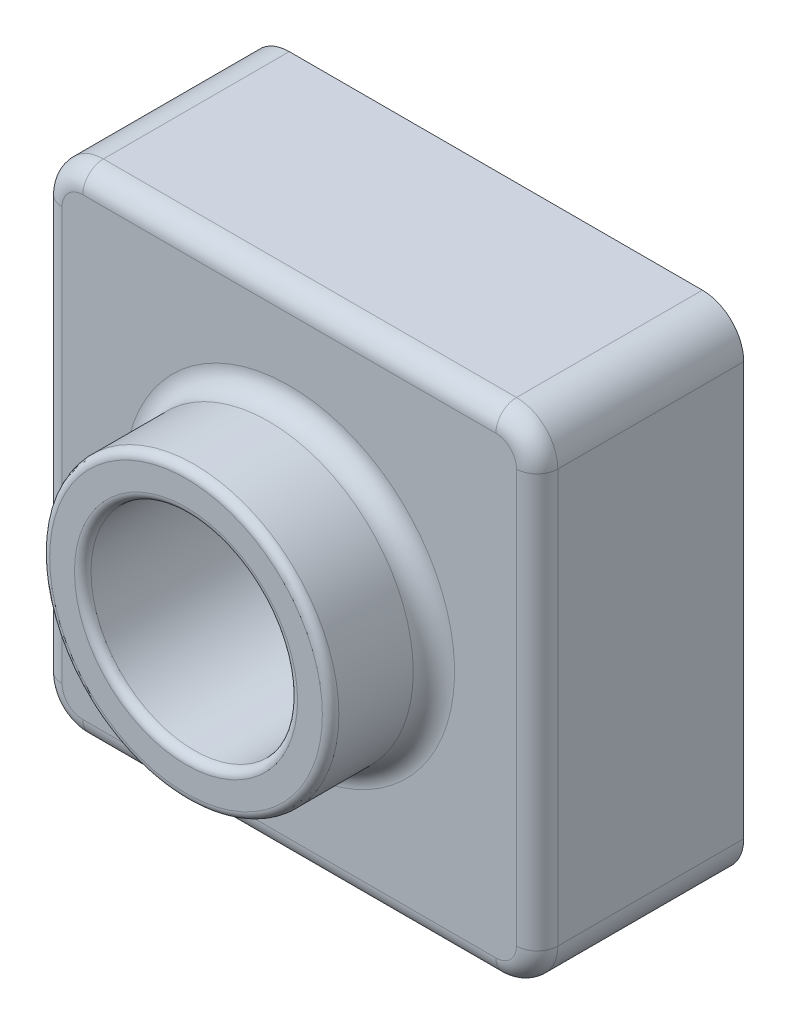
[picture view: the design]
ISO-10303-21;
HEADER;
FILE_DESCRIPTION(('STEP AP214'),'2;1');
FILE_NAME('part.step','',(''),(''),'','','');
FILE_SCHEMA(('AUTOMOTIVE_DESIGN { 1 0 10303 214 1 1 1 1 }'));
ENDSEC;
DATA;
#1=APPLICATION_CONTEXT('core data for automotive mechanical design processes');
#2=APPLICATION_PROTOCOL_DEFINITION('international standard','automotive_design',2000,#1);
#3=PRODUCT_CONTEXT('',#1,'mechanical');
#4=PRODUCT('Part','Part','',(#3));
#5=PRODUCT_RELATED_PRODUCT_CATEGORY('part','',(#4));
#6=PRODUCT_DEFINITION_FORMATION('','',#4);
#7=PRODUCT_DEFINITION_CONTEXT('part definition',#1,'design');
#8=PRODUCT_DEFINITION('design','',#6,#7);
#9=PRODUCT_DEFINITION_SHAPE('','',#8);
#10=(LENGTH_UNIT() NAMED_UNIT(*) SI_UNIT(.MILLI.,.METRE.));
#11=(NAMED_UNIT(*) PLANE_ANGLE_UNIT() SI_UNIT($,.RADIAN.));
#12=(NAMED_UNIT(*) SI_UNIT($,.STERADIAN.) SOLID_ANGLE_UNIT());
#13=UNCERTAINTY_MEASURE_WITH_UNIT(LENGTH_MEASURE(1.E-05),#10,'distance_accuracy_value','');
#14=(GEOMETRIC_REPRESENTATION_CONTEXT(3) GLOBAL_UNCERTAINTY_ASSIGNED_CONTEXT((#13)) GLOBAL_UNIT_ASSIGNED_CONTEXT((#10,
#11,#12)) REPRESENTATION_CONTEXT('',''));
#15=CARTESIAN_POINT('',(0.,0.,0.));
#16=DIRECTION('',(0.,0.,1.));
#17=DIRECTION('',(1.,0.,0.));
#18=AXIS2_PLACEMENT_3D('',#15,#16,#17);
#19=CARTESIAN_POINT('',(0.,120.,-50.));
#20=DIRECTION('',(0.,0.,-1.));
#21=DIRECTION('',(-1.,0.,0.));
#22=AXIS2_PLACEMENT_3D('',#19,#20,#21);
#23=PLANE('',#22);
#24=DIRECTION('',(-1.,0.,0.));
#25=VECTOR('',#24,1.);
#26=CARTESIAN_POINT('',(0.,120.,-50.));
#27=LINE('',#26,#25);
#28=CARTESIAN_POINT('',(110.,120.,-50.));
#29=VERTEX_POINT('',#28);
#30=CARTESIAN_POINT('',(10.,120.,-50.));
#31=VERTEX_POINT('',#30);
#32=EDGE_CURVE('E336',#29,#31,#27,.T.);
#33=ORIENTED_EDGE('',*,*,#32,.F.);
#34=CARTESIAN_POINT('',(110.,110.,-50.));
#35=DIRECTION('',(0.,0.,-1.));
#36=DIRECTION('',(-1.,0.,0.));
#37=AXIS2_PLACEMENT_3D('',#34,#35,#36);
#38=CIRCLE('',#37,10.);
#39=CARTESIAN_POINT('',(120.,110.,-50.));
#40=VERTEX_POINT('',#39);
#41=EDGE_CURVE('E354',#29,#40,#38,.T.);
#42=ORIENTED_EDGE('',*,*,#41,.T.);
#43=DIRECTION('',(0.,1.,0.));
#44=VECTOR('',#43,1.);
#45=CARTESIAN_POINT('',(120.,0.,-50.));
#46=LINE('',#45,#44);
#47=CARTESIAN_POINT('',(120.,10.,-50.));
#48=VERTEX_POINT('',#47);
#49=EDGE_CURVE('E333',#48,#40,#46,.T.);
#50=ORIENTED_EDGE('',*,*,#49,.F.);
#51=CARTESIAN_POINT('',(110.,10.,-50.));
#52=DIRECTION('',(0.,0.,-1.));
#53=DIRECTION('',(-1.,0.,0.));
#54=AXIS2_PLACEMENT_3D('',#51,#52,#53);
#55=CIRCLE('',#54,10.);
#56=CARTESIAN_POINT('',(110.,0.,-50.));
#57=VERTEX_POINT('',#56);
#58=EDGE_CURVE('E350',#48,#57,#55,.T.);
#59=ORIENTED_EDGE('',*,*,#58,.T.);
#60=DIRECTION('',(1.,0.,0.));
#61=VECTOR('',#60,1.);
#62=CARTESIAN_POINT('',(0.,0.,-50.));
#63=LINE('',#62,#61);
#64=CARTESIAN_POINT('',(10.,0.,-50.));
#65=VERTEX_POINT('',#64);
#66=EDGE_CURVE('E330',#65,#57,#63,.T.);
#67=ORIENTED_EDGE('',*,*,#66,.F.);
#68=CARTESIAN_POINT('',(10.,10.,-50.));
#69=DIRECTION('',(0.,0.,-1.));
#70=DIRECTION('',(-1.,0.,0.));
#71=AXIS2_PLACEMENT_3D('',#68,#69,#70);
#72=CIRCLE('',#71,10.);
#73=CARTESIAN_POINT('',(0.,10.,-50.));
#74=VERTEX_POINT('',#73);
#75=EDGE_CURVE('E348',#65,#74,#72,.T.);
#76=ORIENTED_EDGE('',*,*,#75,.T.);
#77=DIRECTION('',(0.,-1.,0.));
#78=VECTOR('',#77,1.);
#79=CARTESIAN_POINT('',(0.,0.,-50.));
#80=LINE('',#79,#78);
#81=CARTESIAN_POINT('',(0.,110.,-50.));
#82=VERTEX_POINT('',#81);
#83=EDGE_CURVE('E326',#82,#74,#80,.T.);
#84=ORIENTED_EDGE('',*,*,#83,.F.);
#85=CARTESIAN_POINT('',(10.,110.,-50.));
#86=DIRECTION('',(0.,0.,-1.));
#87=DIRECTION('',(-1.,0.,0.));
#88=AXIS2_PLACEMENT_3D('',#85,#86,#87);
#89=CIRCLE('',#88,10.);
#90=EDGE_CURVE('E352',#82,#31,#89,.T.);
#91=ORIENTED_EDGE('',*,*,#90,.T.);
#92=EDGE_LOOP('',(#33,#42,#50,#59,#67,#76,#84,#91));
#93=FACE_BOUND('',#92,.T.);
#94=CARTESIAN_POINT('',(110.,110.,-50.));
#95=DIRECTION('',(0.,0.,-1.));
#96=DIRECTION('',(-1.,0.,0.));
#97=AXIS2_PLACEMENT_3D('',#94,#95,#96);
#98=CIRCLE('',#97,6.);
#99=CARTESIAN_POINT('',(110.,116.,-50.));
#100=VERTEX_POINT('',#99);
#101=CARTESIAN_POINT('',(116.,110.,-50.));
#102=VERTEX_POINT('',#101);
#103=EDGE_CURVE('E270',#100,#102,#98,.T.);
#104=ORIENTED_EDGE('',*,*,#103,.F.);
#105=DIRECTION('',(-1.,0.,0.));
#106=VECTOR('',#105,1.);
#107=CARTESIAN_POINT('',(0.,116.,-50.));
#108=LINE('',#107,#106);
#109=CARTESIAN_POINT('',(10.,116.,-50.));
#110=VERTEX_POINT('',#109);
#111=EDGE_CURVE('E290',#100,#110,#108,.T.);
#112=ORIENTED_EDGE('',*,*,#111,.T.);
#113=CARTESIAN_POINT('',(10.,110.,-50.));
#114=DIRECTION('',(0.,0.,-1.));
#115=DIRECTION('',(-1.,0.,0.));
#116=AXIS2_PLACEMENT_3D('',#113,#114,#115);
#117=CIRCLE('',#116,6.);
#118=CARTESIAN_POINT('',(4.,110.,-50.));
#119=VERTEX_POINT('',#118);
#120=EDGE_CURVE('E310',#119,#110,#117,.T.);
#121=ORIENTED_EDGE('',*,*,#120,.F.);
#122=DIRECTION('',(0.,-1.,0.));
#123=VECTOR('',#122,1.);
#124=CARTESIAN_POINT('',(4.,0.,-50.));
#125=LINE('',#124,#123);
#126=CARTESIAN_POINT('',(4.,10.,-50.));
#127=VERTEX_POINT('',#126);
#128=EDGE_CURVE('E49',#119,#127,#125,.T.);
#129=ORIENTED_EDGE('',*,*,#128,.T.);
#130=CARTESIAN_POINT('',(10.,10.,-50.));
#131=DIRECTION('',(0.,0.,-1.));
#132=DIRECTION('',(-1.,0.,0.));
#133=AXIS2_PLACEMENT_3D('',#130,#131,#132);
#134=CIRCLE('',#133,6.);
#135=CARTESIAN_POINT('',(10.,4.,-50.));
#136=VERTEX_POINT('',#135);
#137=EDGE_CURVE('E283',#136,#127,#134,.T.);
#138=ORIENTED_EDGE('',*,*,#137,.F.);
#139=DIRECTION('',(1.,0.,0.));
#140=VECTOR('',#139,1.);
#141=CARTESIAN_POINT('',(0.,4.,-50.));
#142=LINE('',#141,#140);
#143=CARTESIAN_POINT('',(110.,4.,-50.));
#144=VERTEX_POINT('',#143);
#145=EDGE_CURVE('E309',#136,#144,#142,.T.);
#146=ORIENTED_EDGE('',*,*,#145,.T.);
#147=CARTESIAN_POINT('',(110.,10.,-50.));
#148=DIRECTION('',(0.,0.,-1.));
#149=DIRECTION('',(-1.,0.,0.));
#150=AXIS2_PLACEMENT_3D('',#147,#148,#149);
#151=CIRCLE('',#150,6.);
#152=CARTESIAN_POINT('',(116.,10.,-50.));
#153=VERTEX_POINT('',#152);
#154=EDGE_CURVE('E312',#153,#144,#151,.T.);
#155=ORIENTED_EDGE('',*,*,#154,.F.);
#156=DIRECTION('',(0.,1.,0.));
#157=VECTOR('',#156,1.);
#158=CARTESIAN_POINT('',(116.,0.,-50.));
#159=LINE('',#158,#157);
#160=EDGE_CURVE('E315',#153,#102,#159,.T.);
#161=ORIENTED_EDGE('',*,*,#160,.T.);
#162=EDGE_LOOP('',(#104,#112,#121,#129,#138,#146,#155,#161));
#163=FACE_BOUND('',#162,.T.);
#164=ADVANCED_FACE('F34',(#93,#163),#23,.T.);
#165=CARTESIAN_POINT('',(0.,120.,0.));
#166=DIRECTION('',(0.,0.,-1.));
#167=DIRECTION('',(-1.,0.,0.));
#168=AXIS2_PLACEMENT_3D('',#165,#166,#167);
#169=PLANE('',#168);
#170=CARTESIAN_POINT('',(60.,60.,0.));
#171=DIRECTION('',(0.,0.,-1.));
#172=DIRECTION('',(-1.,0.,0.));
#173=AXIS2_PLACEMENT_3D('',#170,#171,#172);
#174=CIRCLE('',#173,40.);
#175=CARTESIAN_POINT('',(20.,60.,0.));
#176=VERTEX_POINT('',#175);
#177=EDGE_CURVE('E386',#176,#176,#174,.T.);
#178=ORIENTED_EDGE('',*,*,#177,.T.);
#179=EDGE_LOOP('',(#178));
#180=FACE_BOUND('',#179,.T.);
#181=DIRECTION('',(1.,0.,0.));
#182=VECTOR('',#181,1.);
#183=CARTESIAN_POINT('',(110.,5.,0.));
#184=LINE('',#183,#182);
#185=CARTESIAN_POINT('',(10.,5.,0.));
#186=VERTEX_POINT('',#185);
#187=CARTESIAN_POINT('',(110.,5.,0.));
#188=VERTEX_POINT('',#187);
#189=EDGE_CURVE('E381',#186,#188,#184,.T.);
#190=ORIENTED_EDGE('',*,*,#189,.T.);
#191=CARTESIAN_POINT('',(110.,10.,0.));
#192=DIRECTION('',(0.,0.,-1.));
#193=DIRECTION('',(-1.,0.,0.));
#194=AXIS2_PLACEMENT_3D('',#191,#192,#193);
#195=CIRCLE('',#194,5.);
#196=CARTESIAN_POINT('',(115.,10.,0.));
#197=VERTEX_POINT('',#196);
#198=EDGE_CURVE('E383',#188,#197,#195,.F.);
#199=ORIENTED_EDGE('',*,*,#198,.T.);
#200=DIRECTION('',(0.,1.,0.));
#201=VECTOR('',#200,1.);
#202=CARTESIAN_POINT('',(115.,110.,0.));
#203=LINE('',#202,#201);
#204=CARTESIAN_POINT('',(115.,110.,0.));
#205=VERTEX_POINT('',#204);
#206=EDGE_CURVE('E369',#197,#205,#203,.T.);
#207=ORIENTED_EDGE('',*,*,#206,.T.);
#208=CARTESIAN_POINT('',(110.,110.,0.));
#209=DIRECTION('',(0.,0.,-1.));
#210=DIRECTION('',(-1.,0.,0.));
#211=AXIS2_PLACEMENT_3D('',#208,#209,#210);
#212=CIRCLE('',#211,5.);
#213=CARTESIAN_POINT('',(110.,115.,0.));
#214=VERTEX_POINT('',#213);
#215=EDGE_CURVE('E371',#205,#214,#212,.F.);
#216=ORIENTED_EDGE('',*,*,#215,.T.);
#217=DIRECTION('',(-1.,0.,0.));
#218=VECTOR('',#217,1.);
#219=CARTESIAN_POINT('',(10.,115.,0.));
#220=LINE('',#219,#218);
#221=CARTESIAN_POINT('',(10.,115.,0.));
#222=VERTEX_POINT('',#221);
#223=EDGE_CURVE('E373',#214,#222,#220,.T.);
#224=ORIENTED_EDGE('',*,*,#223,.T.);
#225=CARTESIAN_POINT('',(10.,110.,0.));
#226=DIRECTION('',(0.,0.,-1.));
#227=DIRECTION('',(-1.,0.,0.));
#228=AXIS2_PLACEMENT_3D('',#225,#226,#227);
#229=CIRCLE('',#228,5.);
#230=CARTESIAN_POINT('',(5.,110.,0.));
#231=VERTEX_POINT('',#230);
#232=EDGE_CURVE('E375',#222,#231,#229,.F.);
#233=ORIENTED_EDGE('',*,*,#232,.T.);
#234=DIRECTION('',(0.,-1.,0.));
#235=VECTOR('',#234,1.);
#236=CARTESIAN_POINT('',(5.,9.99999999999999,0.));
#237=LINE('',#236,#235);
#238=CARTESIAN_POINT('',(5.,10.,0.));
#239=VERTEX_POINT('',#238);
#240=EDGE_CURVE('E377',#231,#239,#237,.T.);
#241=ORIENTED_EDGE('',*,*,#240,.T.);
#242=CARTESIAN_POINT('',(10.,10.,0.));
#243=DIRECTION('',(0.,0.,-1.));
#244=DIRECTION('',(-1.,0.,0.));
#245=AXIS2_PLACEMENT_3D('',#242,#243,#244);
#246=CIRCLE('',#245,5.);
#247=EDGE_CURVE('E379',#239,#186,#246,.F.);
#248=ORIENTED_EDGE('',*,*,#247,.T.);
#249=EDGE_LOOP('',(#190,#199,#207,#216,#224,#233,#241,#248));
#250=FACE_BOUND('',#249,.T.);
#251=ADVANCED_FACE('F475',(#180,#250),#169,.F.);
#252=CARTESIAN_POINT('',(0.,0.,-50.));
#253=DIRECTION('',(-1.,0.,0.));
#254=DIRECTION('',(0.,0.,1.));
#255=AXIS2_PLACEMENT_3D('',#252,#253,#254);
#256=PLANE('',#255);
#257=DIRECTION('',(0.,0.,1.));
#258=VECTOR('',#257,1.);
#259=CARTESIAN_POINT('',(0.,10.,-50.));
#260=LINE('',#259,#258);
#261=CARTESIAN_POINT('',(0.,10.,-5.));
#262=VERTEX_POINT('',#261);
#263=EDGE_CURVE('E356',#74,#262,#260,.T.);
#264=ORIENTED_EDGE('',*,*,#263,.T.);
#265=DIRECTION('',(0.,-1.,0.));
#266=VECTOR('',#265,1.);
#267=CARTESIAN_POINT('',(0.,110.,-5.));
#268=LINE('',#267,#266);
#269=CARTESIAN_POINT('',(0.,110.,-5.));
#270=VERTEX_POINT('',#269);
#271=EDGE_CURVE('E396',#262,#270,#268,.F.);
#272=ORIENTED_EDGE('',*,*,#271,.T.);
#273=DIRECTION('',(0.,0.,1.));
#274=VECTOR('',#273,1.);
#275=CARTESIAN_POINT('',(0.,110.,-50.));
#276=LINE('',#275,#274);
#277=EDGE_CURVE('E359',#270,#82,#276,.F.);
#278=ORIENTED_EDGE('',*,*,#277,.T.);
#279=ORIENTED_EDGE('',*,*,#83,.T.);
#280=EDGE_LOOP('',(#264,#272,#278,#279));
#281=FACE_BOUND('',#280,.T.);
#282=ADVANCED_FACE('F480',(#281),#256,.T.);
#283=CARTESIAN_POINT('',(0.,120.,-50.));
#284=DIRECTION('',(0.,1.,0.));
#285=DIRECTION('',(0.,0.,1.));
#286=AXIS2_PLACEMENT_3D('',#283,#284,#285);
#287=PLANE('',#286);
#288=DIRECTION('',(0.,0.,1.));
#289=VECTOR('',#288,1.);
#290=CARTESIAN_POINT('',(10.,120.,-50.));
#291=LINE('',#290,#289);
#292=CARTESIAN_POINT('',(10.,120.,-5.));
#293=VERTEX_POINT('',#292);
#294=EDGE_CURVE('E343',#31,#293,#291,.T.);
#295=ORIENTED_EDGE('',*,*,#294,.T.);
#296=DIRECTION('',(-1.,0.,0.));
#297=VECTOR('',#296,1.);
#298=CARTESIAN_POINT('',(110.,120.,-5.));
#299=LINE('',#298,#297);
#300=CARTESIAN_POINT('',(110.,120.,-5.));
#301=VERTEX_POINT('',#300);
#302=EDGE_CURVE('E400',#293,#301,#299,.F.);
#303=ORIENTED_EDGE('',*,*,#302,.T.);
#304=DIRECTION('',(0.,0.,1.));
#305=VECTOR('',#304,1.);
#306=CARTESIAN_POINT('',(110.,120.,-50.));
#307=LINE('',#306,#305);
#308=EDGE_CURVE('E346',#301,#29,#307,.F.);
#309=ORIENTED_EDGE('',*,*,#308,.T.);
#310=ORIENTED_EDGE('',*,*,#32,.T.);
#311=EDGE_LOOP('',(#295,#303,#309,#310));
#312=FACE_BOUND('',#311,.T.);
#313=ADVANCED_FACE('F885',(#312),#287,.T.);
#314=CARTESIAN_POINT('',(120.,0.,-50.));
#315=DIRECTION('',(1.,0.,0.));
#316=DIRECTION('',(0.,0.,-1.));
#317=AXIS2_PLACEMENT_3D('',#314,#315,#316);
#318=PLANE('',#317);
#319=DIRECTION('',(0.,0.,1.));
#320=VECTOR('',#319,1.);
#321=CARTESIAN_POINT('',(120.,110.,-50.));
#322=LINE('',#321,#320);
#323=CARTESIAN_POINT('',(120.,110.,-5.));
#324=VERTEX_POINT('',#323);
#325=EDGE_CURVE('E341',#40,#324,#322,.T.);
#326=ORIENTED_EDGE('',*,*,#325,.T.);
#327=DIRECTION('',(0.,1.,0.));
#328=VECTOR('',#327,1.);
#329=CARTESIAN_POINT('',(120.,9.99999999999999,-5.));
#330=LINE('',#329,#328);
#331=CARTESIAN_POINT('',(120.,10.,-5.));
#332=VERTEX_POINT('',#331);
#333=EDGE_CURVE('E403',#324,#332,#330,.F.);
#334=ORIENTED_EDGE('',*,*,#333,.T.);
#335=DIRECTION('',(0.,0.,1.));
#336=VECTOR('',#335,1.);
#337=CARTESIAN_POINT('',(120.,10.,-50.));
#338=LINE('',#337,#336);
#339=EDGE_CURVE('E339',#332,#48,#338,.F.);
#340=ORIENTED_EDGE('',*,*,#339,.T.);
#341=ORIENTED_EDGE('',*,*,#49,.T.);
#342=EDGE_LOOP('',(#326,#334,#340,#341));
#343=FACE_BOUND('',#342,.T.);
#344=ADVANCED_FACE('F469',(#343),#318,.T.);
#345=CARTESIAN_POINT('',(0.,0.,-50.));
#346=DIRECTION('',(0.,-1.,0.));
#347=DIRECTION('',(0.,0.,-1.));
#348=AXIS2_PLACEMENT_3D('',#345,#346,#347);
#349=PLANE('',#348);
#350=DIRECTION('',(0.,0.,1.));
#351=VECTOR('',#350,1.);
#352=CARTESIAN_POINT('',(110.,0.,-50.));
#353=LINE('',#352,#351);
#354=CARTESIAN_POINT('',(110.,0.,-5.));
#355=VERTEX_POINT('',#354);
#356=EDGE_CURVE('E363',#57,#355,#353,.T.);
#357=ORIENTED_EDGE('',*,*,#356,.T.);
#358=DIRECTION('',(1.,0.,0.));
#359=VECTOR('',#358,1.);
#360=CARTESIAN_POINT('',(10.,0.,-5.));
#361=LINE('',#360,#359);
#362=CARTESIAN_POINT('',(10.,0.,-5.));
#363=VERTEX_POINT('',#362);
#364=EDGE_CURVE('E392',#355,#363,#361,.F.);
#365=ORIENTED_EDGE('',*,*,#364,.T.);
#366=DIRECTION('',(0.,0.,1.));
#367=VECTOR('',#366,1.);
#368=CARTESIAN_POINT('',(10.,0.,-50.));
#369=LINE('',#368,#367);
#370=EDGE_CURVE('E361',#363,#65,#369,.F.);
#371=ORIENTED_EDGE('',*,*,#370,.T.);
#372=ORIENTED_EDGE('',*,*,#66,.T.);
#373=EDGE_LOOP('',(#357,#365,#371,#372));
#374=FACE_BOUND('',#373,.T.);
#375=ADVANCED_FACE('F461',(#374),#349,.T.);
#376=CARTESIAN_POINT('',(60.,60.,-50.));
#377=DIRECTION('',(0.,0.,-1.));
#378=DIRECTION('',(-1.,0.,0.));
#379=AXIS2_PLACEMENT_3D('',#376,#377,#378);
#380=CIRCLE('',#379,29.);
#381=CARTESIAN_POINT('',(31.,60.,-50.));
#382=VERTEX_POINT('',#381);
#383=EDGE_CURVE('E265',#382,#382,#380,.F.);
#384=ORIENTED_EDGE('',*,*,#383,.F.);
#385=EDGE_LOOP('',(#384));
#386=FACE_BOUND('',#385,.T.);
#387=CARTESIAN_POINT('',(60.,60.,-50.));
#388=DIRECTION('',(0.,0.,1.));
#389=DIRECTION('',(1.,0.,0.));
#390=AXIS2_PLACEMENT_3D('',#387,#388,#389);
#391=CIRCLE('',#390,25.);
#392=CARTESIAN_POINT('',(85.,60.,-50.));
#393=VERTEX_POINT('',#392);
#394=EDGE_CURVE('E323',#393,#393,#391,.T.);
#395=ORIENTED_EDGE('',*,*,#394,.T.);
#396=EDGE_LOOP('',(#395));
#397=FACE_BOUND('',#396,.T.);
#398=ADVANCED_FACE('F459',(#386,#397),#23,.T.);
#399=CARTESIAN_POINT('',(60.,60.,25.));
#400=DIRECTION('',(0.,0.,-1.));
#401=DIRECTION('',(-1.,0.,0.));
#402=AXIS2_PLACEMENT_3D('',#399,#400,#401);
#403=CYLINDRICAL_SURFACE('',#402,35.);
#404=CARTESIAN_POINT('',(60.,60.,23.));
#405=DIRECTION('',(0.,0.,1.));
#406=DIRECTION('',(1.,0.,0.));
#407=AXIS2_PLACEMENT_3D('',#404,#405,#406);
#408=CIRCLE('',#407,35.);
#409=CARTESIAN_POINT('',(95.,60.,23.));
#410=VERTEX_POINT('',#409);
#411=EDGE_CURVE('E42',#410,#410,#408,.F.);
#412=ORIENTED_EDGE('',*,*,#411,.T.);
#413=EDGE_LOOP('',(#412));
#414=FACE_BOUND('',#413,.T.);
#415=CARTESIAN_POINT('',(60.,60.,5.));
#416=DIRECTION('',(0.,0.,-1.));
#417=DIRECTION('',(-1.,0.,0.));
#418=AXIS2_PLACEMENT_3D('',#415,#416,#417);
#419=CIRCLE('',#418,35.);
#420=CARTESIAN_POINT('',(25.,60.,5.));
#421=VERTEX_POINT('',#420);
#422=EDGE_CURVE('E366',#421,#421,#419,.F.);
#423=ORIENTED_EDGE('',*,*,#422,.T.);
#424=EDGE_LOOP('',(#423));
#425=FACE_BOUND('',#424,.T.);
#426=ADVANCED_FACE('F433',(#414,#425),#403,.T.);
#427=CARTESIAN_POINT('',(60.,60.,25.));
#428=DIRECTION('',(0.,0.,1.));
#429=DIRECTION('',(1.,0.,0.));
#430=AXIS2_PLACEMENT_3D('',#427,#428,#429);
#431=PLANE('',#430);
#432=CARTESIAN_POINT('',(60.,60.,25.));
#433=DIRECTION('',(0.,0.,1.));
#434=DIRECTION('',(1.,0.,0.));
#435=AXIS2_PLACEMENT_3D('',#432,#433,#434);
#436=CIRCLE('',#435,33.);
#437=CARTESIAN_POINT('',(93.,60.,25.));
#438=VERTEX_POINT('',#437);
#439=EDGE_CURVE('E428',#438,#438,#436,.T.);
#440=ORIENTED_EDGE('',*,*,#439,.T.);
#441=EDGE_LOOP('',(#440));
#442=FACE_BOUND('',#441,.T.);
#443=CARTESIAN_POINT('',(60.,60.,25.));
#444=DIRECTION('',(0.,0.,1.));
#445=DIRECTION('',(1.,0.,0.));
#446=AXIS2_PLACEMENT_3D('',#443,#444,#445);
#447=CIRCLE('',#446,27.);
#448=CARTESIAN_POINT('',(87.,60.,25.));
#449=VERTEX_POINT('',#448);
#450=EDGE_CURVE('E405',#449,#449,#447,.F.);
#451=ORIENTED_EDGE('',*,*,#450,.T.);
#452=EDGE_LOOP('',(#451));
#453=FACE_BOUND('',#452,.T.);
#454=ADVANCED_FACE('F442',(#442,#453),#431,.T.);
#455=CARTESIAN_POINT('',(60.,60.,-50.));
#456=DIRECTION('',(0.,0.,1.));
#457=DIRECTION('',(1.,0.,0.));
#458=AXIS2_PLACEMENT_3D('',#455,#456,#457);
#459=CYLINDRICAL_SURFACE('',#458,25.);
#460=CARTESIAN_POINT('',(60.,60.,23.));
#461=DIRECTION('',(0.,0.,1.));
#462=DIRECTION('',(1.,0.,0.));
#463=AXIS2_PLACEMENT_3D('',#460,#461,#462);
#464=CIRCLE('',#463,25.);
#465=CARTESIAN_POINT('',(85.,60.,23.));
#466=VERTEX_POINT('',#465);
#467=EDGE_CURVE('E11',#466,#466,#464,.T.);
#468=ORIENTED_EDGE('',*,*,#467,.T.);
#469=EDGE_LOOP('',(#468));
#470=FACE_BOUND('',#469,.T.);
#471=ORIENTED_EDGE('',*,*,#394,.F.);
#472=EDGE_LOOP('',(#471));
#473=FACE_BOUND('',#472,.T.);
#474=ADVANCED_FACE('F445',(#470,#473),#459,.F.);
#475=CARTESIAN_POINT('',(110.,110.,-50.));
#476=DIRECTION('',(0.,0.,1.));
#477=DIRECTION('',(1.,0.,0.));
#478=AXIS2_PLACEMENT_3D('',#475,#476,#477);
#479=CYLINDRICAL_SURFACE('',#478,10.);
#480=ORIENTED_EDGE('',*,*,#308,.F.);
#481=CARTESIAN_POINT('',(110.,110.,-5.));
#482=DIRECTION('',(0.,0.,-1.));
#483=DIRECTION('',(-1.,0.,0.));
#484=AXIS2_PLACEMENT_3D('',#481,#482,#483);
#485=CIRCLE('',#484,10.);
#486=EDGE_CURVE('E57',#301,#324,#485,.T.);
#487=ORIENTED_EDGE('',*,*,#486,.T.);
#488=ORIENTED_EDGE('',*,*,#325,.F.);
#489=ORIENTED_EDGE('',*,*,#41,.F.);
#490=EDGE_LOOP('',(#480,#487,#488,#489));
#491=FACE_BOUND('',#490,.T.);
#492=ADVANCED_FACE('F455',(#491),#479,.T.);
#493=CARTESIAN_POINT('',(10.,110.,-50.));
#494=DIRECTION('',(0.,0.,1.));
#495=DIRECTION('',(1.,0.,0.));
#496=AXIS2_PLACEMENT_3D('',#493,#494,#495);
#497=CYLINDRICAL_SURFACE('',#496,10.);
#498=ORIENTED_EDGE('',*,*,#277,.F.);
#499=CARTESIAN_POINT('',(10.,110.,-5.));
#500=DIRECTION('',(0.,0.,-1.));
#501=DIRECTION('',(-1.,0.,0.));
#502=AXIS2_PLACEMENT_3D('',#499,#500,#501);
#503=CIRCLE('',#502,10.);
#504=EDGE_CURVE('E398',#270,#293,#503,.T.);
#505=ORIENTED_EDGE('',*,*,#504,.T.);
#506=ORIENTED_EDGE('',*,*,#294,.F.);
#507=ORIENTED_EDGE('',*,*,#90,.F.);
#508=EDGE_LOOP('',(#498,#505,#506,#507));
#509=FACE_BOUND('',#508,.T.);
#510=ADVANCED_FACE('F855',(#509),#497,.T.);
#511=CARTESIAN_POINT('',(110.,10.,-50.));
#512=DIRECTION('',(0.,0.,1.));
#513=DIRECTION('',(1.,0.,0.));
#514=AXIS2_PLACEMENT_3D('',#511,#512,#513);
#515=CYLINDRICAL_SURFACE('',#514,10.);
#516=ORIENTED_EDGE('',*,*,#339,.F.);
#517=CARTESIAN_POINT('',(110.,10.,-5.));
#518=DIRECTION('',(0.,0.,-1.));
#519=DIRECTION('',(-1.,0.,0.));
#520=AXIS2_PLACEMENT_3D('',#517,#518,#519);
#521=CIRCLE('',#520,10.);
#522=EDGE_CURVE('E389',#332,#355,#521,.T.);
#523=ORIENTED_EDGE('',*,*,#522,.T.);
#524=ORIENTED_EDGE('',*,*,#356,.F.);
#525=ORIENTED_EDGE('',*,*,#58,.F.);
#526=EDGE_LOOP('',(#516,#523,#524,#525));
#527=FACE_BOUND('',#526,.T.);
#528=ADVANCED_FACE('F845',(#527),#515,.T.);
#529=CARTESIAN_POINT('',(10.,10.,-50.));
#530=DIRECTION('',(0.,0.,1.));
#531=DIRECTION('',(1.,0.,0.));
#532=AXIS2_PLACEMENT_3D('',#529,#530,#531);
#533=CYLINDRICAL_SURFACE('',#532,10.);
#534=ORIENTED_EDGE('',*,*,#370,.F.);
#535=CARTESIAN_POINT('',(10.,10.,-5.));
#536=DIRECTION('',(0.,0.,-1.));
#537=DIRECTION('',(-1.,0.,0.));
#538=AXIS2_PLACEMENT_3D('',#535,#536,#537);
#539=CIRCLE('',#538,10.);
#540=EDGE_CURVE('E394',#363,#262,#539,.T.);
#541=ORIENTED_EDGE('',*,*,#540,.T.);
#542=ORIENTED_EDGE('',*,*,#263,.F.);
#543=ORIENTED_EDGE('',*,*,#75,.F.);
#544=EDGE_LOOP('',(#534,#541,#542,#543));
#545=FACE_BOUND('',#544,.T.);
#546=ADVANCED_FACE('F835',(#545),#533,.T.);
#547=CARTESIAN_POINT('',(60.,60.,5.));
#548=DIRECTION('',(0.,0.,-1.));
#549=DIRECTION('',(-1.,0.,0.));
#550=AXIS2_PLACEMENT_3D('',#547,#548,#549);
#551=TOROIDAL_SURFACE('',#550,40.,5.);
#552=ORIENTED_EDGE('',*,*,#177,.F.);
#553=EDGE_LOOP('',(#552));
#554=FACE_BOUND('',#553,.T.);
#555=ORIENTED_EDGE('',*,*,#422,.F.);
#556=EDGE_LOOP('',(#555));
#557=FACE_BOUND('',#556,.T.);
#558=ADVANCED_FACE('F824',(#554,#557),#551,.F.);
#559=CARTESIAN_POINT('',(10.,110.,-5.));
#560=DIRECTION('',(0.,0.,-1.));
#561=DIRECTION('',(-1.,0.,0.));
#562=AXIS2_PLACEMENT_3D('',#559,#560,#561);
#563=DEGENERATE_TOROIDAL_SURFACE('',#562,5.,5.,.T.);
#564=CARTESIAN_POINT('',(10.,115.,-5.));
#565=DIRECTION('',(1.,0.,0.));
#566=DIRECTION('',(0.,0.,-1.));
#567=AXIS2_PLACEMENT_3D('',#564,#565,#566);
#568=CIRCLE('',#567,5.);
#569=EDGE_CURVE('E421',#293,#222,#568,.T.);
#570=ORIENTED_EDGE('',*,*,#569,.F.);
#571=ORIENTED_EDGE('',*,*,#504,.F.);
#572=CARTESIAN_POINT('',(5.,110.,-5.));
#573=DIRECTION('',(0.,-1.,0.));
#574=DIRECTION('',(0.,0.,-1.));
#575=AXIS2_PLACEMENT_3D('',#572,#573,#574);
#576=CIRCLE('',#575,5.);
#577=EDGE_CURVE('E327',#231,#270,#576,.T.);
#578=ORIENTED_EDGE('',*,*,#577,.F.);
#579=ORIENTED_EDGE('',*,*,#232,.F.);
#580=EDGE_LOOP('',(#570,#571,#578,#579));
#581=FACE_BOUND('',#580,.T.);
#582=ADVANCED_FACE('F814',(#581),#563,.T.);
#583=CARTESIAN_POINT('',(5.,120.,-5.));
#584=DIRECTION('',(0.,1.,0.));
#585=DIRECTION('',(0.,0.,1.));
#586=AXIS2_PLACEMENT_3D('',#583,#584,#585);
#587=CYLINDRICAL_SURFACE('',#586,5.);
#588=ORIENTED_EDGE('',*,*,#577,.T.);
#589=ORIENTED_EDGE('',*,*,#271,.F.);
#590=CARTESIAN_POINT('',(5.,10.,-5.));
#591=DIRECTION('',(0.,-1.,0.));
#592=DIRECTION('',(0.,0.,-1.));
#593=AXIS2_PLACEMENT_3D('',#590,#591,#592);
#594=CIRCLE('',#593,5.);
#595=EDGE_CURVE('E418',#239,#262,#594,.T.);
#596=ORIENTED_EDGE('',*,*,#595,.F.);
#597=ORIENTED_EDGE('',*,*,#240,.F.);
#598=EDGE_LOOP('',(#588,#589,#596,#597));
#599=FACE_BOUND('',#598,.T.);
#600=ADVANCED_FACE('F804',(#599),#587,.T.);
#601=CARTESIAN_POINT('',(0.,115.,-5.));
#602=DIRECTION('',(1.,0.,0.));
#603=DIRECTION('',(0.,0.,-1.));
#604=AXIS2_PLACEMENT_3D('',#601,#602,#603);
#605=CYLINDRICAL_SURFACE('',#604,5.);
#606=ORIENTED_EDGE('',*,*,#569,.T.);
#607=ORIENTED_EDGE('',*,*,#223,.F.);
#608=CARTESIAN_POINT('',(110.,115.,-5.));
#609=DIRECTION('',(1.,0.,0.));
#610=DIRECTION('',(0.,0.,-1.));
#611=AXIS2_PLACEMENT_3D('',#608,#609,#610);
#612=CIRCLE('',#611,5.);
#613=EDGE_CURVE('E415',#301,#214,#612,.T.);
#614=ORIENTED_EDGE('',*,*,#613,.F.);
#615=ORIENTED_EDGE('',*,*,#302,.F.);
#616=EDGE_LOOP('',(#606,#607,#614,#615));
#617=FACE_BOUND('',#616,.T.);
#618=ADVANCED_FACE('F793',(#617),#605,.T.);
#619=CARTESIAN_POINT('',(10.,10.,-5.));
#620=DIRECTION('',(0.,0.,-1.));
#621=DIRECTION('',(-1.,0.,0.));
#622=AXIS2_PLACEMENT_3D('',#619,#620,#621);
#623=DEGENERATE_TOROIDAL_SURFACE('',#622,5.,5.,.T.);
#624=ORIENTED_EDGE('',*,*,#595,.T.);
#625=ORIENTED_EDGE('',*,*,#540,.F.);
#626=CARTESIAN_POINT('',(10.,5.,-5.));
#627=DIRECTION('',(1.,0.,0.));
#628=DIRECTION('',(0.,0.,-1.));
#629=AXIS2_PLACEMENT_3D('',#626,#627,#628);
#630=CIRCLE('',#629,5.);
#631=EDGE_CURVE('E412',#186,#363,#630,.T.);
#632=ORIENTED_EDGE('',*,*,#631,.F.);
#633=ORIENTED_EDGE('',*,*,#247,.F.);
#634=EDGE_LOOP('',(#624,#625,#632,#633));
#635=FACE_BOUND('',#634,.T.);
#636=ADVANCED_FACE('F782',(#635),#623,.T.);
#637=CARTESIAN_POINT('',(110.,110.,-5.));
#638=DIRECTION('',(0.,0.,-1.));
#639=DIRECTION('',(-1.,0.,0.));
#640=AXIS2_PLACEMENT_3D('',#637,#638,#639);
#641=DEGENERATE_TOROIDAL_SURFACE('',#640,5.,5.,.T.);
#642=ORIENTED_EDGE('',*,*,#613,.T.);
#643=ORIENTED_EDGE('',*,*,#215,.F.);
#644=CARTESIAN_POINT('',(115.,110.,-5.));
#645=DIRECTION('',(0.,-1.,0.));
#646=DIRECTION('',(0.,0.,-1.));
#647=AXIS2_PLACEMENT_3D('',#644,#645,#646);
#648=CIRCLE('',#647,5.);
#649=EDGE_CURVE('E409',#324,#205,#648,.T.);
#650=ORIENTED_EDGE('',*,*,#649,.F.);
#651=ORIENTED_EDGE('',*,*,#486,.F.);
#652=EDGE_LOOP('',(#642,#643,#650,#651));
#653=FACE_BOUND('',#652,.T.);
#654=ADVANCED_FACE('F772',(#653),#641,.T.);
#655=CARTESIAN_POINT('',(0.,5.,-5.));
#656=DIRECTION('',(-1.,0.,0.));
#657=DIRECTION('',(0.,0.,1.));
#658=AXIS2_PLACEMENT_3D('',#655,#656,#657);
#659=CYLINDRICAL_SURFACE('',#658,5.);
#660=ORIENTED_EDGE('',*,*,#631,.T.);
#661=ORIENTED_EDGE('',*,*,#364,.F.);
#662=CARTESIAN_POINT('',(110.,5.,-5.));
#663=DIRECTION('',(1.,0.,0.));
#664=DIRECTION('',(0.,0.,-1.));
#665=AXIS2_PLACEMENT_3D('',#662,#663,#664);
#666=CIRCLE('',#665,5.);
#667=EDGE_CURVE('E407',#188,#355,#666,.T.);
#668=ORIENTED_EDGE('',*,*,#667,.F.);
#669=ORIENTED_EDGE('',*,*,#189,.F.);
#670=EDGE_LOOP('',(#660,#661,#668,#669));
#671=FACE_BOUND('',#670,.T.);
#672=ADVANCED_FACE('F762',(#671),#659,.T.);
#673=CARTESIAN_POINT('',(115.,120.,-5.));
#674=DIRECTION('',(0.,-1.,0.));
#675=DIRECTION('',(0.,0.,-1.));
#676=AXIS2_PLACEMENT_3D('',#673,#674,#675);
#677=CYLINDRICAL_SURFACE('',#676,5.);
#678=ORIENTED_EDGE('',*,*,#649,.T.);
#679=ORIENTED_EDGE('',*,*,#206,.F.);
#680=CARTESIAN_POINT('',(115.,10.,-5.));
#681=DIRECTION('',(0.,-1.,0.));
#682=DIRECTION('',(0.,0.,-1.));
#683=AXIS2_PLACEMENT_3D('',#680,#681,#682);
#684=CIRCLE('',#683,5.);
#685=EDGE_CURVE('E253',#332,#197,#684,.T.);
#686=ORIENTED_EDGE('',*,*,#685,.F.);
#687=ORIENTED_EDGE('',*,*,#333,.F.);
#688=EDGE_LOOP('',(#678,#679,#686,#687));
#689=FACE_BOUND('',#688,.T.);
#690=ADVANCED_FACE('F751',(#689),#677,.T.);
#691=CARTESIAN_POINT('',(110.,10.,-5.));
#692=DIRECTION('',(0.,0.,-1.));
#693=DIRECTION('',(-1.,0.,0.));
#694=AXIS2_PLACEMENT_3D('',#691,#692,#693);
#695=DEGENERATE_TOROIDAL_SURFACE('',#694,5.,5.,.T.);
#696=ORIENTED_EDGE('',*,*,#667,.T.);
#697=ORIENTED_EDGE('',*,*,#522,.F.);
#698=ORIENTED_EDGE('',*,*,#685,.T.);
#699=ORIENTED_EDGE('',*,*,#198,.F.);
#700=EDGE_LOOP('',(#696,#697,#698,#699));
#701=FACE_BOUND('',#700,.T.);
#702=ADVANCED_FACE('F439',(#701),#695,.T.);
#703=CARTESIAN_POINT('',(60.,60.,23.));
#704=DIRECTION('',(0.,0.,1.));
#705=DIRECTION('',(1.,0.,0.));
#706=AXIS2_PLACEMENT_3D('',#703,#704,#705);
#707=TOROIDAL_SURFACE('',#706,33.,2.);
#708=ORIENTED_EDGE('',*,*,#411,.F.);
#709=EDGE_LOOP('',(#708));
#710=FACE_BOUND('',#709,.T.);
#711=ORIENTED_EDGE('',*,*,#439,.F.);
#712=EDGE_LOOP('',(#711));
#713=FACE_BOUND('',#712,.T.);
#714=ADVANCED_FACE('F436',(#710,#713),#707,.T.);
#715=CARTESIAN_POINT('',(60.,60.,23.));
#716=DIRECTION('',(0.,0.,1.));
#717=DIRECTION('',(1.,0.,0.));
#718=AXIS2_PLACEMENT_3D('',#715,#716,#717);
#719=TOROIDAL_SURFACE('',#718,27.,2.);
#720=ORIENTED_EDGE('',*,*,#450,.F.);
#721=EDGE_LOOP('',(#720));
#722=FACE_BOUND('',#721,.T.);
#723=ORIENTED_EDGE('',*,*,#467,.F.);
#724=EDGE_LOOP('',(#723));
#725=FACE_BOUND('',#724,.T.);
#726=ADVANCED_FACE('F36',(#722,#725),#719,.T.);
#727=CARTESIAN_POINT('',(0.,120.,-4.));
#728=DIRECTION('',(0.,0.,-1.));
#729=DIRECTION('',(-1.,0.,0.));
#730=AXIS2_PLACEMENT_3D('',#727,#728,#729);
#731=PLANE('',#730);
#732=CARTESIAN_POINT('',(60.,60.,-4.));
#733=DIRECTION('',(0.,0.,-1.));
#734=DIRECTION('',(-1.,0.,0.));
#735=AXIS2_PLACEMENT_3D('',#732,#733,#734);
#736=CIRCLE('',#735,40.);
#737=CARTESIAN_POINT('',(20.,60.,-4.));
#738=VERTEX_POINT('',#737);
#739=EDGE_CURVE('E227',#738,#738,#736,.T.);
#740=ORIENTED_EDGE('',*,*,#739,.F.);
#741=EDGE_LOOP('',(#740));
#742=FACE_BOUND('',#741,.T.);
#743=DIRECTION('',(-1.,0.,0.));
#744=VECTOR('',#743,1.);
#745=CARTESIAN_POINT('',(0.,5.,-4.));
#746=LINE('',#745,#744);
#747=CARTESIAN_POINT('',(10.,5.,-4.));
#748=VERTEX_POINT('',#747);
#749=CARTESIAN_POINT('',(110.,5.,-4.));
#750=VERTEX_POINT('',#749);
#751=EDGE_CURVE('E199',#748,#750,#746,.F.);
#752=ORIENTED_EDGE('',*,*,#751,.F.);
#753=CARTESIAN_POINT('',(10.,10.,-4.));
#754=DIRECTION('',(0.,0.,-1.));
#755=DIRECTION('',(-1.,0.,0.));
#756=AXIS2_PLACEMENT_3D('',#753,#754,#755);
#757=CIRCLE('',#756,5.);
#758=CARTESIAN_POINT('',(5.,9.99999999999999,-4.));
#759=VERTEX_POINT('',#758);
#760=EDGE_CURVE('E210',#759,#748,#757,.F.);
#761=ORIENTED_EDGE('',*,*,#760,.F.);
#762=DIRECTION('',(0.,1.,0.));
#763=VECTOR('',#762,1.);
#764=CARTESIAN_POINT('',(5.,120.,-4.));
#765=LINE('',#764,#763);
#766=CARTESIAN_POINT('',(5.,110.,-4.));
#767=VERTEX_POINT('',#766);
#768=EDGE_CURVE('E240',#767,#759,#765,.F.);
#769=ORIENTED_EDGE('',*,*,#768,.F.);
#770=CARTESIAN_POINT('',(10.,110.,-4.));
#771=DIRECTION('',(0.,0.,-1.));
#772=DIRECTION('',(-1.,0.,0.));
#773=AXIS2_PLACEMENT_3D('',#770,#771,#772);
#774=CIRCLE('',#773,5.);
#775=CARTESIAN_POINT('',(10.,115.,-4.));
#776=VERTEX_POINT('',#775);
#777=EDGE_CURVE('E238',#776,#767,#774,.F.);
#778=ORIENTED_EDGE('',*,*,#777,.F.);
#779=DIRECTION('',(-1.,0.,0.));
#780=VECTOR('',#779,1.);
#781=CARTESIAN_POINT('',(0.,115.,-4.));
#782=LINE('',#781,#780);
#783=CARTESIAN_POINT('',(110.,115.,-4.));
#784=VERTEX_POINT('',#783);
#785=EDGE_CURVE('E236',#784,#776,#782,.T.);
#786=ORIENTED_EDGE('',*,*,#785,.F.);
#787=CARTESIAN_POINT('',(110.,110.,-4.));
#788=DIRECTION('',(0.,0.,-1.));
#789=DIRECTION('',(-1.,0.,0.));
#790=AXIS2_PLACEMENT_3D('',#787,#788,#789);
#791=CIRCLE('',#790,5.);
#792=CARTESIAN_POINT('',(115.,110.,-4.));
#793=VERTEX_POINT('',#792);
#794=EDGE_CURVE('E233',#793,#784,#791,.F.);
#795=ORIENTED_EDGE('',*,*,#794,.F.);
#796=DIRECTION('',(0.,1.,0.));
#797=VECTOR('',#796,1.);
#798=CARTESIAN_POINT('',(115.,120.,-4.));
#799=LINE('',#798,#797);
#800=CARTESIAN_POINT('',(115.,10.,-4.));
#801=VERTEX_POINT('',#800);
#802=EDGE_CURVE('E226',#801,#793,#799,.T.);
#803=ORIENTED_EDGE('',*,*,#802,.F.);
#804=CARTESIAN_POINT('',(110.,10.,-4.));
#805=DIRECTION('',(0.,0.,-1.));
#806=DIRECTION('',(-1.,0.,0.));
#807=AXIS2_PLACEMENT_3D('',#804,#805,#806);
#808=CIRCLE('',#807,5.);
#809=EDGE_CURVE('E209',#750,#801,#808,.F.);
#810=ORIENTED_EDGE('',*,*,#809,.F.);
#811=EDGE_LOOP('',(#752,#761,#769,#778,#786,#795,#803,#810));
#812=FACE_BOUND('',#811,.T.);
#813=ADVANCED_FACE('F224',(#742,#812),#731,.T.);
#814=CARTESIAN_POINT('',(4.,0.,-50.));
#815=DIRECTION('',(-1.,0.,0.));
#816=DIRECTION('',(0.,0.,1.));
#817=AXIS2_PLACEMENT_3D('',#814,#815,#816);
#818=PLANE('',#817);
#819=DIRECTION('',(0.,0.,1.));
#820=VECTOR('',#819,1.);
#821=CARTESIAN_POINT('',(4.,10.,-50.));
#822=LINE('',#821,#820);
#823=CARTESIAN_POINT('',(4.,10.,-5.));
#824=VERTEX_POINT('',#823);
#825=EDGE_CURVE('E266',#127,#824,#822,.T.);
#826=ORIENTED_EDGE('',*,*,#825,.F.);
#827=ORIENTED_EDGE('',*,*,#128,.F.);
#828=DIRECTION('',(0.,0.,1.));
#829=VECTOR('',#828,1.);
#830=CARTESIAN_POINT('',(4.,110.,-50.));
#831=LINE('',#830,#829);
#832=CARTESIAN_POINT('',(4.,110.,-5.));
#833=VERTEX_POINT('',#832);
#834=EDGE_CURVE('E269',#833,#119,#831,.F.);
#835=ORIENTED_EDGE('',*,*,#834,.F.);
#836=DIRECTION('',(0.,1.,0.));
#837=VECTOR('',#836,1.);
#838=CARTESIAN_POINT('',(4.,0.,-5.));
#839=LINE('',#838,#837);
#840=EDGE_CURVE('E262',#824,#833,#839,.T.);
#841=ORIENTED_EDGE('',*,*,#840,.F.);
#842=EDGE_LOOP('',(#826,#827,#835,#841));
#843=FACE_BOUND('',#842,.T.);
#844=ADVANCED_FACE('F524',(#843),#818,.F.);
#845=CARTESIAN_POINT('',(0.,116.,-50.));
#846=DIRECTION('',(0.,1.,0.));
#847=DIRECTION('',(0.,0.,1.));
#848=AXIS2_PLACEMENT_3D('',#845,#846,#847);
#849=PLANE('',#848);
#850=DIRECTION('',(0.,0.,1.));
#851=VECTOR('',#850,1.);
#852=CARTESIAN_POINT('',(10.,116.,-50.));
#853=LINE('',#852,#851);
#854=CARTESIAN_POINT('',(10.,116.,-5.));
#855=VERTEX_POINT('',#854);
#856=EDGE_CURVE('E275',#110,#855,#853,.T.);
#857=ORIENTED_EDGE('',*,*,#856,.F.);
#858=ORIENTED_EDGE('',*,*,#111,.F.);
#859=DIRECTION('',(0.,0.,1.));
#860=VECTOR('',#859,1.);
#861=CARTESIAN_POINT('',(110.,116.,-50.));
#862=LINE('',#861,#860);
#863=CARTESIAN_POINT('',(110.,116.,-5.));
#864=VERTEX_POINT('',#863);
#865=EDGE_CURVE('E278',#864,#100,#862,.F.);
#866=ORIENTED_EDGE('',*,*,#865,.F.);
#867=DIRECTION('',(1.,0.,0.));
#868=VECTOR('',#867,1.);
#869=CARTESIAN_POINT('',(0.,116.,-5.));
#870=LINE('',#869,#868);
#871=EDGE_CURVE('E261',#855,#864,#870,.T.);
#872=ORIENTED_EDGE('',*,*,#871,.F.);
#873=EDGE_LOOP('',(#857,#858,#866,#872));
#874=FACE_BOUND('',#873,.T.);
#875=ADVANCED_FACE('F513',(#874),#849,.F.);
#876=CARTESIAN_POINT('',(116.,0.,-50.));
#877=DIRECTION('',(1.,0.,0.));
#878=DIRECTION('',(0.,0.,-1.));
#879=AXIS2_PLACEMENT_3D('',#876,#877,#878);
#880=PLANE('',#879);
#881=DIRECTION('',(0.,0.,-1.));
#882=VECTOR('',#881,1.);
#883=CARTESIAN_POINT('',(116.,110.,-50.));
#884=LINE('',#883,#882);
#885=CARTESIAN_POINT('',(116.,110.,-5.));
#886=VERTEX_POINT('',#885);
#887=EDGE_CURVE('E279',#102,#886,#884,.F.);
#888=ORIENTED_EDGE('',*,*,#887,.F.);
#889=ORIENTED_EDGE('',*,*,#160,.F.);
#890=DIRECTION('',(0.,0.,-1.));
#891=VECTOR('',#890,1.);
#892=CARTESIAN_POINT('',(116.,10.,-50.));
#893=LINE('',#892,#891);
#894=CARTESIAN_POINT('',(116.,10.,-5.));
#895=VERTEX_POINT('',#894);
#896=EDGE_CURVE('E287',#895,#153,#893,.T.);
#897=ORIENTED_EDGE('',*,*,#896,.F.);
#898=DIRECTION('',(0.,1.,0.));
#899=VECTOR('',#898,1.);
#900=CARTESIAN_POINT('',(116.,0.,-5.));
#901=LINE('',#900,#899);
#902=EDGE_CURVE('E250',#886,#895,#901,.F.);
#903=ORIENTED_EDGE('',*,*,#902,.F.);
#904=EDGE_LOOP('',(#888,#889,#897,#903));
#905=FACE_BOUND('',#904,.T.);
#906=ADVANCED_FACE('F498',(#905),#880,.F.);
#907=CARTESIAN_POINT('',(0.,4.,-50.));
#908=DIRECTION('',(0.,-1.,0.));
#909=DIRECTION('',(0.,0.,-1.));
#910=AXIS2_PLACEMENT_3D('',#907,#908,#909);
#911=PLANE('',#910);
#912=DIRECTION('',(0.,0.,-1.));
#913=VECTOR('',#912,1.);
#914=CARTESIAN_POINT('',(110.,4.,-50.));
#915=LINE('',#914,#913);
#916=CARTESIAN_POINT('',(110.,4.,-5.));
#917=VERTEX_POINT('',#916);
#918=EDGE_CURVE('E245',#144,#917,#915,.F.);
#919=ORIENTED_EDGE('',*,*,#918,.F.);
#920=ORIENTED_EDGE('',*,*,#145,.F.);
#921=DIRECTION('',(0.,0.,-1.));
#922=VECTOR('',#921,1.);
#923=CARTESIAN_POINT('',(10.,4.,-50.));
#924=LINE('',#923,#922);
#925=CARTESIAN_POINT('',(10.,4.,-5.));
#926=VERTEX_POINT('',#925);
#927=EDGE_CURVE('E274',#926,#136,#924,.T.);
#928=ORIENTED_EDGE('',*,*,#927,.F.);
#929=DIRECTION('',(1.,0.,0.));
#930=VECTOR('',#929,1.);
#931=CARTESIAN_POINT('',(0.,4.,-5.));
#932=LINE('',#931,#930);
#933=EDGE_CURVE('E292',#917,#926,#932,.F.);
#934=ORIENTED_EDGE('',*,*,#933,.F.);
#935=EDGE_LOOP('',(#919,#920,#928,#934));
#936=FACE_BOUND('',#935,.T.);
#937=ADVANCED_FACE('F657',(#936),#911,.F.);
#938=CARTESIAN_POINT('',(60.,60.,25.));
#939=DIRECTION('',(0.,0.,-1.));
#940=DIRECTION('',(-1.,0.,0.));
#941=AXIS2_PLACEMENT_3D('',#938,#939,#940);
#942=CYLINDRICAL_SURFACE('',#941,31.);
#943=CARTESIAN_POINT('',(60.,60.,21.));
#944=DIRECTION('',(0.,0.,1.));
#945=DIRECTION('',(1.,0.,0.));
#946=AXIS2_PLACEMENT_3D('',#943,#944,#945);
#947=CIRCLE('',#946,31.);
#948=CARTESIAN_POINT('',(91.,60.,21.));
#949=VERTEX_POINT('',#948);
#950=EDGE_CURVE('E246',#949,#949,#947,.T.);
#951=ORIENTED_EDGE('',*,*,#950,.T.);
#952=EDGE_LOOP('',(#951));
#953=FACE_BOUND('',#952,.T.);
#954=CARTESIAN_POINT('',(60.,60.,5.));
#955=DIRECTION('',(0.,0.,-1.));
#956=DIRECTION('',(-1.,0.,0.));
#957=AXIS2_PLACEMENT_3D('',#954,#955,#956);
#958=CIRCLE('',#957,31.);
#959=CARTESIAN_POINT('',(29.,60.,5.));
#960=VERTEX_POINT('',#959);
#961=EDGE_CURVE('E234',#960,#960,#958,.F.);
#962=ORIENTED_EDGE('',*,*,#961,.F.);
#963=EDGE_LOOP('',(#962));
#964=FACE_BOUND('',#963,.T.);
#965=ADVANCED_FACE('F647',(#953,#964),#942,.F.);
#966=CARTESIAN_POINT('',(60.,60.,21.));
#967=DIRECTION('',(0.,0.,1.));
#968=DIRECTION('',(1.,0.,0.));
#969=AXIS2_PLACEMENT_3D('',#966,#967,#968);
#970=PLANE('',#969);
#971=ORIENTED_EDGE('',*,*,#950,.F.);
#972=EDGE_LOOP('',(#971));
#973=FACE_BOUND('',#972,.T.);
#974=CARTESIAN_POINT('',(60.,60.,21.));
#975=DIRECTION('',(0.,0.,1.));
#976=DIRECTION('',(1.,0.,0.));
#977=AXIS2_PLACEMENT_3D('',#974,#975,#976);
#978=CIRCLE('',#977,29.);
#979=CARTESIAN_POINT('',(89.,60.,21.));
#980=VERTEX_POINT('',#979);
#981=EDGE_CURVE('E249',#980,#980,#978,.T.);
#982=ORIENTED_EDGE('',*,*,#981,.T.);
#983=EDGE_LOOP('',(#982));
#984=FACE_BOUND('',#983,.T.);
#985=ADVANCED_FACE('F637',(#973,#984),#970,.F.);
#986=CARTESIAN_POINT('',(60.,60.,-50.));
#987=DIRECTION('',(0.,0.,1.));
#988=DIRECTION('',(1.,0.,0.));
#989=AXIS2_PLACEMENT_3D('',#986,#987,#988);
#990=CYLINDRICAL_SURFACE('',#989,29.);
#991=ORIENTED_EDGE('',*,*,#981,.F.);
#992=EDGE_LOOP('',(#991));
#993=FACE_BOUND('',#992,.T.);
#994=ORIENTED_EDGE('',*,*,#383,.T.);
#995=EDGE_LOOP('',(#994));
#996=FACE_BOUND('',#995,.T.);
#997=ADVANCED_FACE('F628',(#993,#996),#990,.T.);
#998=CARTESIAN_POINT('',(110.,110.,-50.));
#999=DIRECTION('',(0.,0.,1.));
#1000=DIRECTION('',(1.,0.,0.));
#1001=AXIS2_PLACEMENT_3D('',#998,#999,#1000);
#1002=CYLINDRICAL_SURFACE('',#1001,6.);
#1003=ORIENTED_EDGE('',*,*,#865,.T.);
#1004=ORIENTED_EDGE('',*,*,#103,.T.);
#1005=ORIENTED_EDGE('',*,*,#887,.T.);
#1006=CARTESIAN_POINT('',(110.,110.,-5.));
#1007=DIRECTION('',(0.,0.,1.));
#1008=DIRECTION('',(1.,0.,0.));
#1009=AXIS2_PLACEMENT_3D('',#1006,#1007,#1008);
#1010=CIRCLE('',#1009,6.);
#1011=EDGE_CURVE('E281',#864,#886,#1010,.F.);
#1012=ORIENTED_EDGE('',*,*,#1011,.F.);
#1013=EDGE_LOOP('',(#1003,#1004,#1005,#1012));
#1014=FACE_BOUND('',#1013,.T.);
#1015=ADVANCED_FACE('F492',(#1014),#1002,.F.);
#1016=CARTESIAN_POINT('',(10.,110.,-50.));
#1017=DIRECTION('',(0.,0.,1.));
#1018=DIRECTION('',(1.,0.,0.));
#1019=AXIS2_PLACEMENT_3D('',#1016,#1017,#1018);
#1020=CYLINDRICAL_SURFACE('',#1019,6.);
#1021=ORIENTED_EDGE('',*,*,#834,.T.);
#1022=ORIENTED_EDGE('',*,*,#120,.T.);
#1023=ORIENTED_EDGE('',*,*,#856,.T.);
#1024=CARTESIAN_POINT('',(10.,110.,-5.));
#1025=DIRECTION('',(0.,0.,1.));
#1026=DIRECTION('',(1.,0.,0.));
#1027=AXIS2_PLACEMENT_3D('',#1024,#1025,#1026);
#1028=CIRCLE('',#1027,6.);
#1029=EDGE_CURVE('E259',#833,#855,#1028,.F.);
#1030=ORIENTED_EDGE('',*,*,#1029,.F.);
#1031=EDGE_LOOP('',(#1021,#1022,#1023,#1030));
#1032=FACE_BOUND('',#1031,.T.);
#1033=ADVANCED_FACE('F516',(#1032),#1020,.F.);
#1034=CARTESIAN_POINT('',(110.,10.,-50.));
#1035=DIRECTION('',(0.,0.,1.));
#1036=DIRECTION('',(1.,0.,0.));
#1037=AXIS2_PLACEMENT_3D('',#1034,#1035,#1036);
#1038=CYLINDRICAL_SURFACE('',#1037,6.);
#1039=ORIENTED_EDGE('',*,*,#896,.T.);
#1040=ORIENTED_EDGE('',*,*,#154,.T.);
#1041=ORIENTED_EDGE('',*,*,#918,.T.);
#1042=CARTESIAN_POINT('',(110.,10.,-5.));
#1043=DIRECTION('',(0.,0.,1.));
#1044=DIRECTION('',(1.,0.,0.));
#1045=AXIS2_PLACEMENT_3D('',#1042,#1043,#1044);
#1046=CIRCLE('',#1045,6.);
#1047=EDGE_CURVE('E218',#895,#917,#1046,.F.);
#1048=ORIENTED_EDGE('',*,*,#1047,.F.);
#1049=EDGE_LOOP('',(#1039,#1040,#1041,#1048));
#1050=FACE_BOUND('',#1049,.T.);
#1051=ADVANCED_FACE('F603',(#1050),#1038,.F.);
#1052=CARTESIAN_POINT('',(10.,10.,-50.));
#1053=DIRECTION('',(0.,0.,1.));
#1054=DIRECTION('',(1.,0.,0.));
#1055=AXIS2_PLACEMENT_3D('',#1052,#1053,#1054);
#1056=CYLINDRICAL_SURFACE('',#1055,6.);
#1057=ORIENTED_EDGE('',*,*,#927,.T.);
#1058=ORIENTED_EDGE('',*,*,#137,.T.);
#1059=ORIENTED_EDGE('',*,*,#825,.T.);
#1060=CARTESIAN_POINT('',(10.,10.,-5.));
#1061=DIRECTION('',(0.,0.,1.));
#1062=DIRECTION('',(1.,0.,0.));
#1063=AXIS2_PLACEMENT_3D('',#1060,#1061,#1062);
#1064=CIRCLE('',#1063,6.);
#1065=EDGE_CURVE('E272',#926,#824,#1064,.F.);
#1066=ORIENTED_EDGE('',*,*,#1065,.F.);
#1067=EDGE_LOOP('',(#1057,#1058,#1059,#1066));
#1068=FACE_BOUND('',#1067,.T.);
#1069=ADVANCED_FACE('F520',(#1068),#1056,.F.);
#1070=CARTESIAN_POINT('',(60.,60.,5.));
#1071=DIRECTION('',(0.,0.,-1.));
#1072=DIRECTION('',(-1.,0.,0.));
#1073=AXIS2_PLACEMENT_3D('',#1070,#1071,#1072);
#1074=TOROIDAL_SURFACE('',#1073,40.,9.);
#1075=ORIENTED_EDGE('',*,*,#739,.T.);
#1076=EDGE_LOOP('',(#1075));
#1077=FACE_BOUND('',#1076,.T.);
#1078=ORIENTED_EDGE('',*,*,#961,.T.);
#1079=EDGE_LOOP('',(#1078));
#1080=FACE_BOUND('',#1079,.T.);
#1081=ADVANCED_FACE('F535',(#1077,#1080),#1074,.T.);
#1082=CARTESIAN_POINT('',(10.,110.,-5.));
#1083=DIRECTION('',(0.,0.,-1.));
#1084=DIRECTION('',(-1.,0.,0.));
#1085=AXIS2_PLACEMENT_3D('',#1082,#1083,#1084);
#1086=TOROIDAL_SURFACE('',#1085,5.,1.);
#1087=CARTESIAN_POINT('',(10.,115.,-5.));
#1088=DIRECTION('',(1.,0.,0.));
#1089=DIRECTION('',(0.,0.,-1.));
#1090=AXIS2_PLACEMENT_3D('',#1087,#1088,#1089);
#1091=CIRCLE('',#1090,1.);
#1092=EDGE_CURVE('E254',#855,#776,#1091,.T.);
#1093=ORIENTED_EDGE('',*,*,#1092,.T.);
#1094=ORIENTED_EDGE('',*,*,#777,.T.);
#1095=CARTESIAN_POINT('',(5.,110.,-5.));
#1096=DIRECTION('',(0.,1.,0.));
#1097=DIRECTION('',(0.,0.,1.));
#1098=AXIS2_PLACEMENT_3D('',#1095,#1096,#1097);
#1099=CIRCLE('',#1098,1.);
#1100=EDGE_CURVE('E257',#767,#833,#1099,.F.);
#1101=ORIENTED_EDGE('',*,*,#1100,.T.);
#1102=ORIENTED_EDGE('',*,*,#1029,.T.);
#1103=EDGE_LOOP('',(#1093,#1094,#1101,#1102));
#1104=FACE_BOUND('',#1103,.T.);
#1105=ADVANCED_FACE('F533',(#1104),#1086,.F.);
#1106=CARTESIAN_POINT('',(5.,120.,-5.));
#1107=DIRECTION('',(0.,1.,0.));
#1108=DIRECTION('',(0.,0.,1.));
#1109=AXIS2_PLACEMENT_3D('',#1106,#1107,#1108);
#1110=CYLINDRICAL_SURFACE('',#1109,1.);
#1111=ORIENTED_EDGE('',*,*,#1100,.F.);
#1112=ORIENTED_EDGE('',*,*,#768,.T.);
#1113=CARTESIAN_POINT('',(5.,10.,-5.));
#1114=DIRECTION('',(0.,-1.,0.));
#1115=DIRECTION('',(0.,0.,-1.));
#1116=AXIS2_PLACEMENT_3D('',#1113,#1114,#1115);
#1117=CIRCLE('',#1116,1.);
#1118=EDGE_CURVE('E258',#759,#824,#1117,.T.);
#1119=ORIENTED_EDGE('',*,*,#1118,.T.);
#1120=ORIENTED_EDGE('',*,*,#840,.T.);
#1121=EDGE_LOOP('',(#1111,#1112,#1119,#1120));
#1122=FACE_BOUND('',#1121,.T.);
#1123=ADVANCED_FACE('F528',(#1122),#1110,.F.);
#1124=CARTESIAN_POINT('',(0.,115.,-5.));
#1125=DIRECTION('',(1.,0.,0.));
#1126=DIRECTION('',(0.,0.,-1.));
#1127=AXIS2_PLACEMENT_3D('',#1124,#1125,#1126);
#1128=CYLINDRICAL_SURFACE('',#1127,1.);
#1129=ORIENTED_EDGE('',*,*,#1092,.F.);
#1130=ORIENTED_EDGE('',*,*,#871,.T.);
#1131=CARTESIAN_POINT('',(110.,115.,-5.));
#1132=DIRECTION('',(-1.,0.,0.));
#1133=DIRECTION('',(0.,-1.,0.));
#1134=AXIS2_PLACEMENT_3D('',#1131,#1132,#1133);
#1135=CIRCLE('',#1134,1.);
#1136=EDGE_CURVE('E299',#864,#784,#1135,.F.);
#1137=ORIENTED_EDGE('',*,*,#1136,.T.);
#1138=ORIENTED_EDGE('',*,*,#785,.T.);
#1139=EDGE_LOOP('',(#1129,#1130,#1137,#1138));
#1140=FACE_BOUND('',#1139,.T.);
#1141=ADVANCED_FACE('F508',(#1140),#1128,.F.);
#1142=CARTESIAN_POINT('',(10.,10.,-5.));
#1143=DIRECTION('',(0.,0.,-1.));
#1144=DIRECTION('',(-1.,0.,0.));
#1145=AXIS2_PLACEMENT_3D('',#1142,#1143,#1144);
#1146=TOROIDAL_SURFACE('',#1145,5.,1.);
#1147=ORIENTED_EDGE('',*,*,#1118,.F.);
#1148=ORIENTED_EDGE('',*,*,#760,.T.);
#1149=CARTESIAN_POINT('',(10.,5.,-5.));
#1150=DIRECTION('',(-1.,0.,0.));
#1151=DIRECTION('',(0.,0.,1.));
#1152=AXIS2_PLACEMENT_3D('',#1149,#1150,#1151);
#1153=CIRCLE('',#1152,1.);
#1154=EDGE_CURVE('E205',#748,#926,#1153,.F.);
#1155=ORIENTED_EDGE('',*,*,#1154,.T.);
#1156=ORIENTED_EDGE('',*,*,#1065,.T.);
#1157=EDGE_LOOP('',(#1147,#1148,#1155,#1156));
#1158=FACE_BOUND('',#1157,.T.);
#1159=ADVANCED_FACE('F531',(#1158),#1146,.F.);
#1160=CARTESIAN_POINT('',(110.,110.,-5.));
#1161=DIRECTION('',(0.,0.,-1.));
#1162=DIRECTION('',(-1.,0.,0.));
#1163=AXIS2_PLACEMENT_3D('',#1160,#1161,#1162);
#1164=TOROIDAL_SURFACE('',#1163,5.,1.);
#1165=ORIENTED_EDGE('',*,*,#1136,.F.);
#1166=ORIENTED_EDGE('',*,*,#1011,.T.);
#1167=CARTESIAN_POINT('',(115.,110.,-5.));
#1168=DIRECTION('',(0.,-1.,0.));
#1169=DIRECTION('',(0.,0.,-1.));
#1170=AXIS2_PLACEMENT_3D('',#1167,#1168,#1169);
#1171=CIRCLE('',#1170,1.);
#1172=EDGE_CURVE('E220',#886,#793,#1171,.T.);
#1173=ORIENTED_EDGE('',*,*,#1172,.T.);
#1174=ORIENTED_EDGE('',*,*,#794,.T.);
#1175=EDGE_LOOP('',(#1165,#1166,#1173,#1174));
#1176=FACE_BOUND('',#1175,.T.);
#1177=ADVANCED_FACE('F504',(#1176),#1164,.F.);
#1178=CARTESIAN_POINT('',(0.,5.,-5.));
#1179=DIRECTION('',(-1.,0.,0.));
#1180=DIRECTION('',(0.,0.,1.));
#1181=AXIS2_PLACEMENT_3D('',#1178,#1179,#1180);
#1182=CYLINDRICAL_SURFACE('',#1181,1.);
#1183=ORIENTED_EDGE('',*,*,#1154,.F.);
#1184=ORIENTED_EDGE('',*,*,#751,.T.);
#1185=CARTESIAN_POINT('',(110.,5.,-5.));
#1186=DIRECTION('',(1.,0.,0.));
#1187=DIRECTION('',(0.,1.,0.));
#1188=AXIS2_PLACEMENT_3D('',#1185,#1186,#1187);
#1189=CIRCLE('',#1188,1.);
#1190=EDGE_CURVE('E202',#750,#917,#1189,.T.);
#1191=ORIENTED_EDGE('',*,*,#1190,.T.);
#1192=ORIENTED_EDGE('',*,*,#933,.T.);
#1193=EDGE_LOOP('',(#1183,#1184,#1191,#1192));
#1194=FACE_BOUND('',#1193,.T.);
#1195=ADVANCED_FACE('F201',(#1194),#1182,.F.);
#1196=CARTESIAN_POINT('',(115.,120.,-5.));
#1197=DIRECTION('',(0.,-1.,0.));
#1198=DIRECTION('',(0.,0.,-1.));
#1199=AXIS2_PLACEMENT_3D('',#1196,#1197,#1198);
#1200=CYLINDRICAL_SURFACE('',#1199,1.);
#1201=ORIENTED_EDGE('',*,*,#1172,.F.);
#1202=ORIENTED_EDGE('',*,*,#902,.T.);
#1203=CARTESIAN_POINT('',(115.,10.,-5.));
#1204=DIRECTION('',(0.,1.,0.));
#1205=DIRECTION('',(-1.,0.,0.));
#1206=AXIS2_PLACEMENT_3D('',#1203,#1204,#1205);
#1207=CIRCLE('',#1206,1.);
#1208=EDGE_CURVE('E221',#895,#801,#1207,.F.);
#1209=ORIENTED_EDGE('',*,*,#1208,.T.);
#1210=ORIENTED_EDGE('',*,*,#802,.T.);
#1211=EDGE_LOOP('',(#1201,#1202,#1209,#1210));
#1212=FACE_BOUND('',#1211,.T.);
#1213=ADVANCED_FACE('F501',(#1212),#1200,.F.);
#1214=CARTESIAN_POINT('',(110.,10.,-5.));
#1215=DIRECTION('',(0.,0.,-1.));
#1216=DIRECTION('',(-1.,0.,0.));
#1217=AXIS2_PLACEMENT_3D('',#1214,#1215,#1216);
#1218=TOROIDAL_SURFACE('',#1217,5.,1.);
#1219=ORIENTED_EDGE('',*,*,#1190,.F.);
#1220=ORIENTED_EDGE('',*,*,#809,.T.);
#1221=ORIENTED_EDGE('',*,*,#1208,.F.);
#1222=ORIENTED_EDGE('',*,*,#1047,.T.);
#1223=EDGE_LOOP('',(#1219,#1220,#1221,#1222));
#1224=FACE_BOUND('',#1223,.T.);
#1225=ADVANCED_FACE('F215',(#1224),#1218,.F.);
#1226=CLOSED_SHELL('',(#164,#251,#282,#313,#344,#375,#398,#426,#454,#474,#492,#510,#528,#546,
#558,#582,#600,#618,#636,#654,#672,#690,#702,#714,#726,#813,#844,#875,#906,#937,#965,#985,#997,
#1015,#1033,#1051,#1069,#1081,#1105,#1123,#1141,#1159,#1177,#1195,#1213,#1225));
#1227=MANIFOLD_SOLID_BREP('B2',#1226);
#1228=ADVANCED_BREP_SHAPE_REPRESENTATION('',(#18,#1227),#14);
#1229=SHAPE_DEFINITION_REPRESENTATION(#9,#1228);
ENDSEC;
END-ISO-10303-21;
